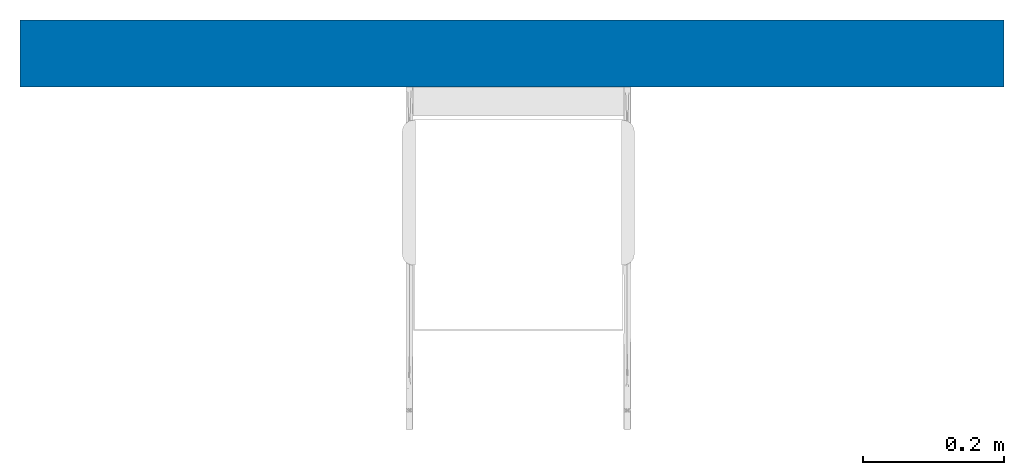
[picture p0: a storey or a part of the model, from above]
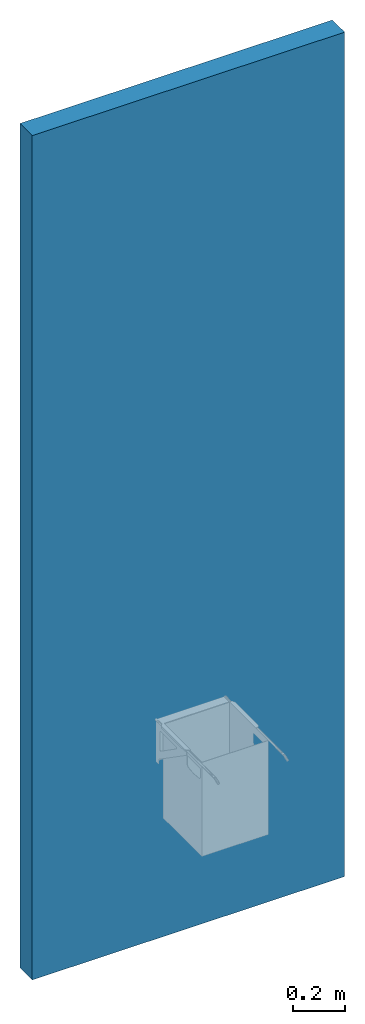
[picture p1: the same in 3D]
Properties of the parts of a building model (IFC2X3)

# File
Description: ViewDefinition [CoordinationView]
File name: Project Number
Time: 2019-04-29T15:53:34
Written by: The EXPRESS Data Manager Version 5.02.0100.07 : 28 Aug 2013
Made in: 20140606_1530(x64) - Exporter 2015.0.2014.0606 - Default UI
Comment: STEP Physical File produced by: The EXPRESS Data Manager Version 5.02.0100.07 : 28 Aug 2013 * Module: EDMstepFileFactory/EDMstandAlone * Creation date: Mon Apr 29 15:53:34 2019 * Host: SarahSams-HP * Database: C:\Users\SARAHS~1\AppData\Local\Temp\{E94398E0-A282-475A-9AEC-91AEDE524A4D}\ifc * Database version: 5507 * Database creation date: Mon Apr 29 15:53:32 2019 * Schema: IFC2X3 * Model: DataRepository.ifc * Model creation date: Mon Apr 29 15:53:32 2019 * Header model: DataRepository.ifc_HeaderModel * Header model creation date: Mon Apr 29 15:53:32 2019 * EDMuser: sdai-user * EDMgroup: sdai-group * License ID and type: 5605 : Permanent license. Expiry date: * EDMstepFileFactory options: 020000

# IfcProject, Project Number
LongName: Project Name; Phase: Project Status

# IfcSite, Default
RefLatitude: 51, 30, 0, 549316; RefLongitude: 0, -7, -34, -450321; RefElevation: 0 mm
Other - Category: Project Information; Client Name: Owner; Project Address: Enter address here; Project Issue Date: Issue Date; Project Name: Project Name; Project Number: Project Number; Project Status: Project Status

# IfcBuilding
Pset_BuildingCommon - NumberOfStoreys: 1
Other - Category: Project Information; Client Name: Owner; Project Address: Enter address here; Project Issue Date: Issue Date; Project Name: Project Name; Project Number: Project Number; Project Status: Project Status

# IfcBuildingStorey, Level 0
LongName: Level 0; Elevation: 0 mm
Other - Category: Levels; Family Name: Level; Family: Level: Circle Head - Project Datum; Family and Type: Level: Circle Head - Project Datum; Type: Level: Circle Head - Project Datum; Type Id: Level: Circle Head - Project Datum
Identity Data - Type Name: Circle Head - Project Datum; Structural: no; Building Story: yes; Name: Level 0
Constraints - Elevation: 0 mm; Elevation Base: Project Base Point
Dimensions - Computation Height: 0 mm
Graphics - Color: 0; Line Pattern: Centre; Line Weight: 1; Symbol: Anno_Level_Head_Circle: Standard; Symbol at End 1 Default: yes; Symbol at End 2 Default: no

# IfcBuildingElementProxy: Brushed Stainless Steel, Duten_LittrBins_P775:Brushed Stainless Steel:263652
In: Level 0
Classification: E2020200 Furniture & Accessories (Uniformat); Material: Duten_Metal_BrushedStainlessSteel
Pset_BuildingElementProxyCommon - Reference: n/a
Pset_ManufacturerTypeInformation - ModelReference: Brushed Stainless Steel; Manufacturer: contact@duten.fr
Constraints - Elevation: 600 mm; Level: Level: Level 0
Dimensions - Area: 0.661576 m2; Volume: 0.000772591 m3
Other - Category: Generic Models; Family: Duten_LittrBins_P775: Brushed Stainless Steel; Family and Type: Duten_LittrBins_P775: Brushed Stainless Steel; Host Id: Basic Wall: Wall-Partn_12P-70MStd-12P; Type: Duten_LittrBins_P775: Brushed Stainless Steel; Type Id: Duten_LittrBins_P775: Brushed Stainless Steel; AccessibilityPerformance: n/a; AssetIdentifier: n/a; AssetType: Moveable; BarCode: n/a; CodePerformance: n/a; Color: Defined by Finish; Constituents: Folded Stainless Steel; DurationUnit: Years; ExpectedLife: 25; Family Name: Duten_LittrBins_P775; Features: 40L under counter waste bin. Can be completely removed for quick and easy emptying. Welded corners, no sharp edges which makes it easy to clean; Finish: Available in Brushed or Polished Stainless Steel; Grade: n/a; InstallationDate: 1900-12-31T23:59:59; Material: Stainless Steel ANSI 304; ModelNumber: P775-S; ModelReference: Brushed Stainless Steel; Name: LitterBins_P775_Duten; ReplacementCost: 0; SerialNumber: n/a; Shape: Rectangle; Size: (H) 448mm x (L) 300mm x (W) 298mm; SustainabilityPerformance: n/a; TagNumber: n/a; WarrantyDescription: n/a; WarrantyDurationLabor: 25; WarrantyDurationParts: 25; WarrantyDurationUnit: Years; WarrantyGuarantorLabor: contact@duten.fr; WarrantyGuarantorParts: contact@duten.fr; WarrantyStartDate: 1900-12-31T23:59:59
Phasing - Phase Created: New Construction
General - Author: Diane Butterworth Ltd; ManufacturerName: Duten; ManufacturerURL: http://www.duten.fr/; NBSDescription: Litter bins; NBSReference: 45-35-86/335; ProductInformation: https://www.duten.fr/produits/poubelles-receptacles/poubelle-tiroir-40l-sous-lavabo-p775; Revision: n/a; Uniclass2015Code: Pr_40_50_07_47; Uniclass2015Title: Litter bins; Uniclass2015Version: Pr-Products v1.10
Identity Data - Assembly Code: E2020200; Assembly Description: Furniture & Accessories; Cost: 0; Description: Brushed Stainless Steel; Keynote: Pr_40_50_07_47; Manufacturer: contact@duten.fr; Model: P775-S; Type Comments: Brushed Stainless Steel; Type Name: Brushed Stainless Steel; URL: http://www.duten.fr/
Materials and Finishes - UnitFinish: Duten_Metal_BrushedStainlessSteel

# IfcWallStandardCase: Basic Wall:Wall-Partn_12P-70MStd-12P, Basic Wall:Wall-Partn_12P-70MStd-12P:261433
In: Level 0
Type - PredefinedType: STANDARD; Material: Plaster 12.5 mm, Metal Stud Layer 70 mm, Plaster 12.5 mm
Type - Analytical Properties - Absorptance: 0.7; Heat Transfer Coefficient (U): 0.350998; Roughness: 3; Thermal mass: 26964.3; Thermal Resistance (R): 2.84902
Type - Construction - Function: Interior; Width: 95 mm; Wrapping at Inserts: Both
Type - Graphics - Coarse Scale Fill Color: 12632256; Coarse Scale Fill Pattern: Solid fill
Type - Identity Data - Type Name: Wall-Partn_12P-70MStd-12P
Type - Other - Category: Walls; Family Name: Basic Wall
Constraints - Base Constraint: Level: Level 0; Base Extension Distance: 0 mm; Base is Attached: no; Base Offset: 0 mm; Location Line: Wall Centerline; Related to Mass: no; Room Bounding: yes; Top Constraint: Level: Level 1; Top Extension Distance: 0 mm; Top is Attached: no; Top Offset: 0 mm; Unconnected Height: 4000 mm
Dimensions - Area: 5.6 m2; Length: 1400 mm; Volume: 0.532 m3
Other - Family: Basic Wall: Wall-Partn_12P-70MStd-12P; Family and Type: Basic Wall: Wall-Partn_12P-70MStd-12P; Type: Basic Wall: Wall-Partn_12P-70MStd-12P; Type Id: Basic Wall: Wall-Partn_12P-70MStd-12P
Phasing - Phase Created: New Construction
Structural - Enable Analytical Model: no; Structural: no; Structural Usage: Non-bearing
Pset_WallCommon - Reference: Wall-Partn_12P-70MStd-12P; LoadBearing: no; ExtendToStructure: no; IsExternal: no; ThermalTransmittance: 0.350998 kg/K/s3
